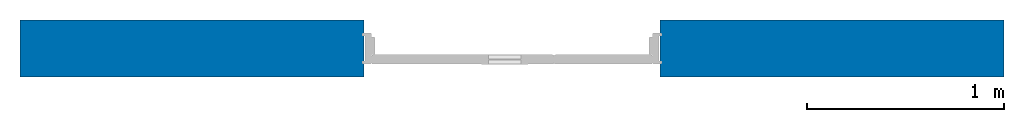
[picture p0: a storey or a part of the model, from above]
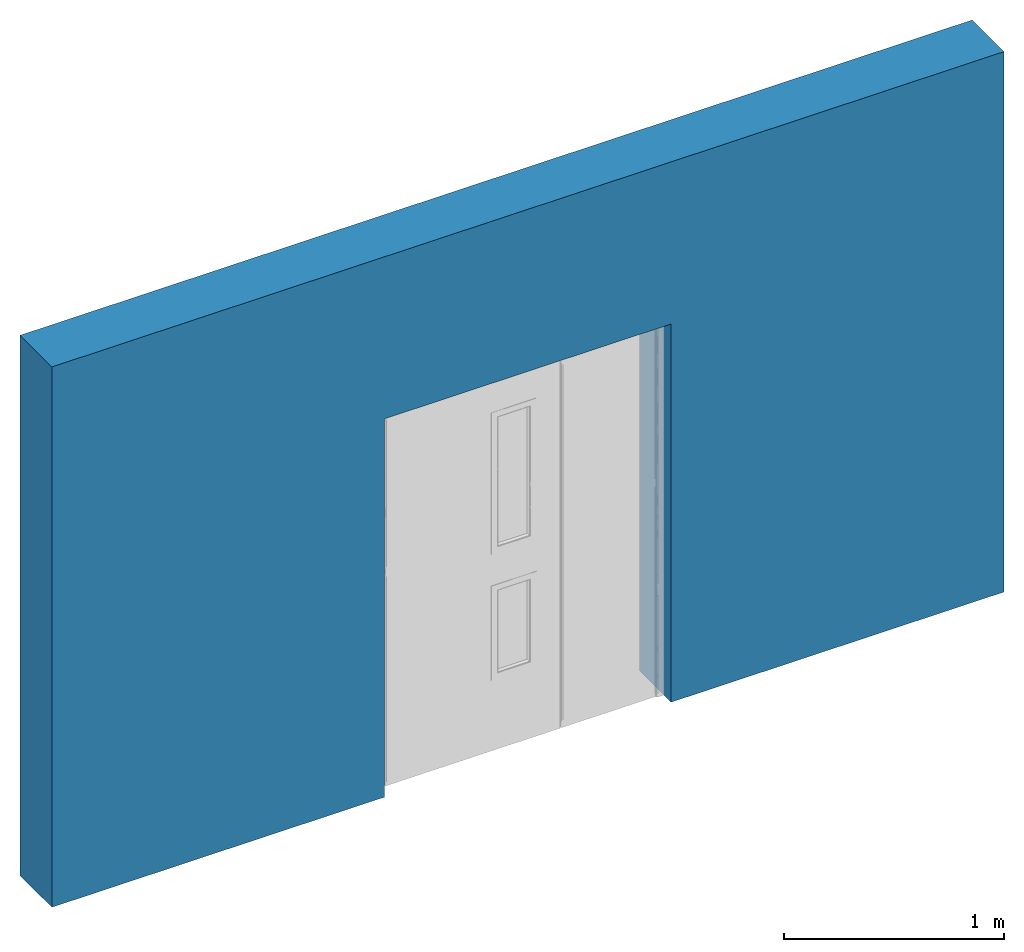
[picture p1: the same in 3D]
Properties of the parts of a building model (IFC2X3)

# File
Description: ViewDefinition [CoordinationView_V2.0]
File name: Project Number
Time: 2016-07-19T10:12:57
Written by: The EXPRESS Data Manager Version 5.01.0100.02.64mod : 6 Jun 2012
Made in: 20131024_2115(x64) - Exporter 3.13.0.0 - Alternate UI 2.13.0.0
Comment: STEP Physical File produced by: The EXPRESS Data Manager Version 5.01.0100.02.64mod : 6 Jun 2012* Module: EDMstepFileFactory/EDMstandAlone* Creation date: Tue Jul 19 10:12:57 2016* Host: ncl-PI11* Database: C:\Users\batyg\AppData\Local\Temp\{9EF77646-CCFF-4BA2-9BEA-A71504FC5203}\ifc* Database version: 5507* Database creation date: Tue Jul 19 10:12:56 2016* Schema: IFC2X3* Model: DataRepository.ifc* Model creation date: Tue Jul 19 10:12:56 2016* Header model: DataRepository.ifc_HeaderModel* Header model creation date: Tue Jul 19 10:12:56 2016* EDMuser: sdai-user* EDMgroup: sdai-group* License ID and type: 5605 : Permanent license. Expiry date: * EDMstepFileFactory options: 020000

# IfcProject, Project Number
LongName: Project Name; Phase: Project Status

# IfcSite, Default
RefLatitude: 51, 30, 0, 549316; RefLongitude: 0, -7, -34, -450321; RefElevation: 0 mm

# IfcBuildingStorey, Level 0
LongName: Level 0; Elevation: 0 mm

# IfcDoor: PostformedOneAndAHalfPairDoorset-VisionPanel3_3Piece_1504x2100mm, NBS_SDSProtectionLtd_CompDrsts_PostformedOneAndAHalfPairDoorset-VisionPanel3:PostformedOneAndAHalfPairDoorset-VisionPanel3_3Piece_1504x2100mm:222081
In: Level 0
Type - OperationType: DOUBLE_DOOR_SINGLE_SWING; ConstructionType: WOOD; ParameterTakesPrecedence: no; Sizeable: no; Material: NBS_Concept, NBS_Glass_Single
Type - NBS_SDSProtectionLtd_CompDrsts_PostformedOneAndAHalfPairDoorset-VisionPanel3:PostformedOneAndAHalfPairDoorset-VisionPanel3_3Piece_1504x2100mm:222081 - PanelOperation: SWINGING
Type - NBS_General - Author: NBS; BIMObjectName: NBS_SDSProtectionLtd_CompositeDoorsets_PostformedOneAndAHalfPairDoorset-VisionPanel3; ManufacturerName: SDS Protection Ltd; ManufacturerURL: www.sdsprotection.co.uk; NBSCertification: http://www.nationalbimlibrary.com/cert/le5tpvgi; NBSDescription: Composite doorsets; NBSNote: n/a; NBSOfficeMasterTag: n/a; NBSReference: 45-25-28/342; NBSTypeID: n/a; ProductInformation: www.sdsprotection.co.uk/doorsets/plastic-encapsulated; Revision: n/a; Uniclass2: 45-60-03/417; Uniclass2015Description: Composite doorsets; Uniclass2015Reference: Pr_30_59_24_16; Uniclass2015Version: Products v1.1; Version: 2
Type - NBS_Data - Accessories: n/a; AcousticPerformanceOptions: Non acoustic rated, 30 dB, 32 dB, 35 dB, 40 dB, 41 dB; AirTransferGrille: no; AirTransferGrilleSize: n/a; AntiFingerTrapRequirement: no; ArchitravesFinishAndColour: Postformed options: dFend encapsulated, durablend™ encapsulated, Hydroclean encapsulated, Woodgrains encapsulated. Postformed colours -consult manufacturer's literature. Other finish options: Lacquered hardwood, Pre-primed; ArchitravesMaterial: Timber core with thermoplastic cover; ArchitravesWoodAppearanceClass: n/a; Configuration: Leaf and part leaf, single action; DoorFrameColourOptions: Extensive range of colours available, Consult manufacturer's literature; DoorFrameFinishOptions: Postformed options: dFend encapsulated, durablend™ encapsulated, Hydroclean encapsulated, Woodgrains encapsulated. Other finish options: Lacquered hardwood, Pre-primed; DoorFrameTypeOptions: Rebated, Split-frame, Traditional; DoorLeafBeadingFixing: n/a; DoorLeafBeadingMaterial: n/a; DoorLeafBeadingType: n/a; DoorLeafCoreOptions: Block, Particle; DoorLeafDoorAccessories: Cappings, Door edge protection, Kickplates; DoorLeafFaceColourOptions: Many options available, consult manufacturer's literature; DoorLeafFaceFinishOptions: dFend, Durablend, Hydroclean; DoorLeafFacingsExternal: 1.5 mm thick thermoplastic; DoorLeafFacingsInternal: 1.5 mm thick thermoplastic; DoorLeafGlazingBeadingOptions: Flushglaze, Overclad; DoorLeafGlazingManifestation: n/a; DoorLeafGlazingSize: 750 x 200 mm and 488 x 200 mm (h x w); DoorLeafGlazingTypeOptions: Clear, Frosted, Smart glass; DoorLeafLippings: n/a; DoorLeafPanelDetails: n/a; DoorLeafPerimeterSeals: To suit fire and acoustic rating; DoorLeafThickness: Non fire rated - 48 mm, FD30 - 48 mm, FD60 - 58 mm; ElectronicLock: no; EnvironmentalProductDeclaration: n/a; FireRatingOptions: Non fire rated, FD30, FD60, Exceptions consult manufacturer; FloorFinish: n/a; FrameAccessories: Alternative frame header thickness to accommodate concealed closers. Timber strip for joining split frames; FrameMaterialOptions: Hardwood, Softwood; FramePerimeterSealsOrInserts: To suit fire and acoustic rating; FrameThreshold: n/a; Handing: Primary leaf handing to be specified; Hardware: Supplied with 25 year guarantee butt hinges; HardwareSet: Supplied with 3 butt hinges (25 year guarantee) per leaf; HeadDetail: n/a; HoldOpen: no; JambDetail: n/a; KeySuiting: n/a; LeafSwing: n/a; OpeningMechanism: no; PerformanceBulletResistance: n/a; PerformanceExplosionResistanceAccessibility: n/a; PerformanceExplosionResistanceBlastDuration: n/a; PerformanceExplosionResistanceOverpressureMaximum: n/a; PerformanceExplosionResistancePressureMode: n/a; PerformanceExplosionResistanceReboundPressureMaximum: n/a; PerformanceRadiation: n/a; PerformanceSmokeControl: n/a; PerformanceStrengthAndDurability: BS EN 1192, Class 4; PerformanceSurfaceSpreadOfFlame: dFend thermoplastic - Class 1; PreservativeTreatment: n/a; SignageFire: n/a; SignageSecurity: n/a; SignageWayfinding: n/a; ThirdPartyAccreditation: IFC, BM Trada
Type - Pset_DoorCommon - AcousticRating: n/a; FireExit: no; FireRating: n/a; GlazingAreaFraction: 0; HandicapAccessible: no; Infiltration: 0 m3/s; IsExternal: no; Reference: n/a; SecurityRating: n/a; SelfClosing: no; SmokeStop: no; ThermalTransmittance: 0 kg/K/s3
Type - Pset_DoorWindowGlazingType - BeamRadiationTransmittance: 0; FillGas: n/a; GlassColour: n/a; GlassLayers: 1; GlassThickness1: 7 mm; GlassThickness2: 0 mm; GlassThickness3: 0 mm; IsCoated: no; IsLaminated: no; IsTempered: no; IsWired: no; Reflectivity: 0; SolarHeatGainTransmittance: 0; ThermalTransmittanceSummer: 0 kg/K/s3; ThermalTransmittanceWinter: 0 kg/K/s3; Translucency: 0
Type - COBie - AccessibilityPerformance: n/a; AssetType: Fixed; Category: Pr_30_59_24_16:Composite doorsets; CodePerformance: n/a; Color: n/a; Constituents: n/a; Description: Postformed one and a half pair doorset; DurationUnit: year; ExpectedLife: In excess of 15 years in normal use; Features: Exceptional durability, Easy maintainance, Hygienic encapsulation assists infection control, Increased service life comparative to traditional doorsets; Finish: Over 60no. dFendor thermoplastic options, consult manufacturer's literature; Grade: n/a; Manufacturer: www.sdsprotection.co.uk; Material: Wood with thermoplastic cladding; ModelNumber: n/a; ModelReference: Postformed One And A Half Pair Doorset - Vision Panel 3; Name: CompositeDoorsets_PostformedOneAndAHalfPairDoorset-VisionPanel3_SDSProtectionLtd; NominalHeight: 2100 mm; NominalLength: 0 mm; NominalWidth: 1504 mm; ReplacementCost: n/a; Shape: n/a; Size: 1504x2100mm; SustainabilityPerformance: n/a; WarrantyDescription: n/a; WarrantyDurationLabor: n/a; WarrantyDurationParts: n/a; WarrantyDurationUnit: year; WarrantyGuarantorLabor: n/a; WarrantyGuarantorParts: n/a
OverallHeight: 2100 mm; OverallWidth: 1504 mm
NBS_Data - ComponentNumber: n/a; DoorNumber: n/a
COBie - AssetIdentifier: n/a; BarCode: n/a; InstallationDate: 1900-12-31T23:59:59; SerialNumber: n/a; TagNumber: n/a; WarrantyStartDate: 1900-12-31T23:59:59

# IfcWallStandardCase: Basic Wall:Cav - 102 75i 100 p - Lwt, Basic Wall:Cav - 102 75i 100 p - Lwt:217121
In: Level 0
Type - PredefinedType: STANDARD; Material: Brick, Common 102.5 mm, Fiberglass Batt 75 mm, Concrete Masonry Units 100 mm, Gypsum Wall Board 12.5 mm
